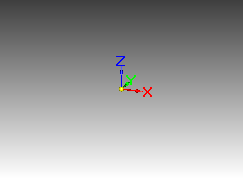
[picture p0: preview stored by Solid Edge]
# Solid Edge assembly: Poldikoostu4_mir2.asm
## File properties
Author: Türk
Template: Iso Assembly.asm
Last saved by: Türk
Revision: 2
Application: Solid Edge
Username: Türk
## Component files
Mutter.par
Polt120x20.par
